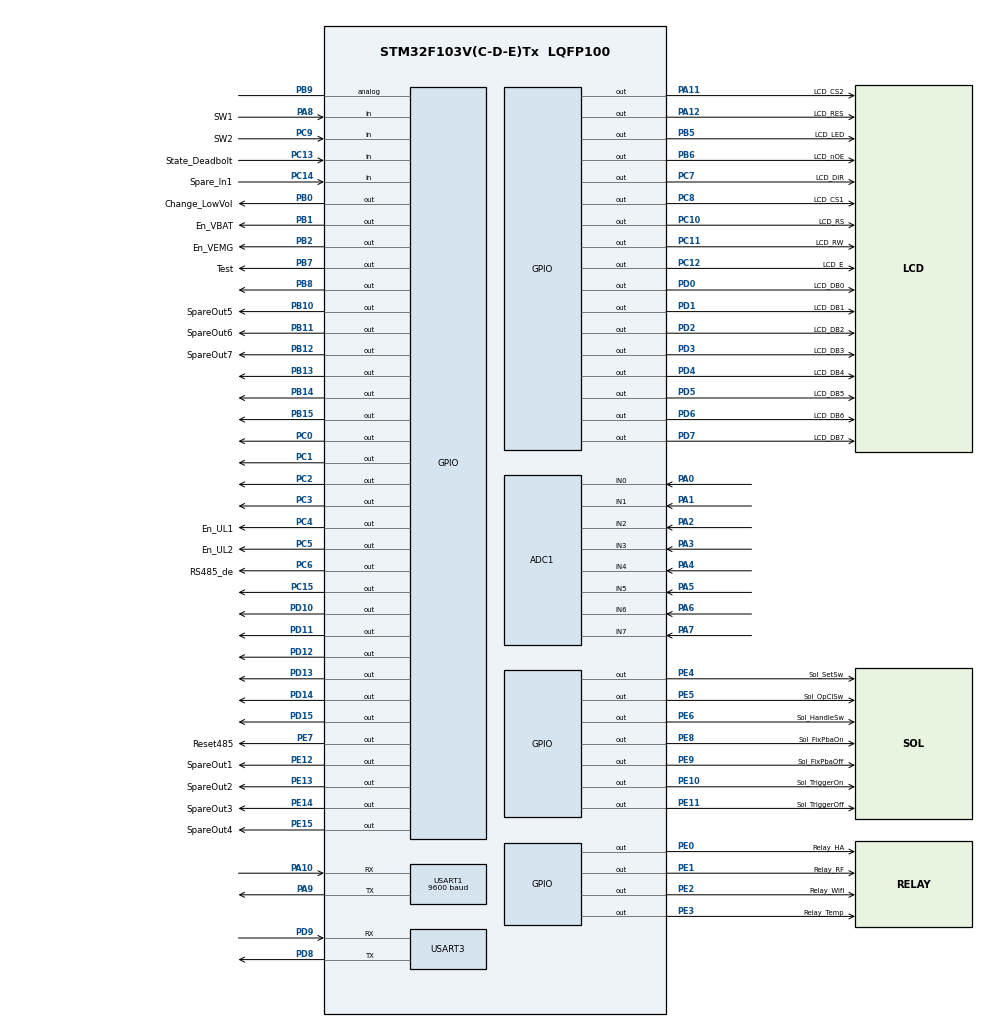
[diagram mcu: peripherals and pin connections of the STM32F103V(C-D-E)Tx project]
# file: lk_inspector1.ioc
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ADC1.Channel-0\#ChannelRegularConversion=ADC_CHANNEL_0
ADC1.NbrOfConversionFlag=1
ADC1.Rank-0\#ChannelRegularConversion=1
ADC1.SamplingTime-0\#ChannelRegularConversion=ADC_SAMPLETIME_1CYCLE_5
ADC1.master=1
FREERTOS.INCLUDE_pcTaskGetTaskName=1
FREERTOS.INCLUDE_xTaskGetCurrentTaskHandle=1
FREERTOS.INCLUDE_xTaskGetHandle=1
FREERTOS.Tasks01=defaultTask,24,128,StartDefaultTask,Default,NULL,Dynamic,NULL,NULL
FREERTOS.configUSE_IDLE_HOOK=1
FREERTOS.configUSE_NEWLIB_REENTRANT=0
Mcu.Family=STM32F1
Mcu.Name=STM32F103V(C-D-E)Tx
Mcu.Package=LQFP100
NVIC.PriorityGroup=NVIC_PRIORITYGROUP_4
NVIC.USART1_IRQn=true\:5\:0\:false\:false\:true\:true\:true\:true
OSC_IN.Mode=HSE-External-Oscillator
OSC_IN.Signal=RCC_OSC_IN
OSC_OUT.Mode=HSE-External-Oscillator
OSC_OUT.Signal=RCC_OSC_OUT
PA0-WKUP.Signal=ADCx_IN0
PA1.Signal=ADCx_IN1
PA10.Mode=Asynchronous
PA10.Signal=USART1_RX
PA11.GPIO_Label=LCD_CS2
PA11.Signal=GPIO_Output
PA12.GPIO_Label=LCD_RES
PA12.Signal=GPIO_Output
PA13.Mode=JTAG_5_pins
PA13.Signal=SYS_JTMS-SWDIO
PA14.Mode=JTAG_5_pins
PA14.Signal=SYS_JTCK-SWCLK
PA15.Mode=JTAG_5_pins
PA15.Signal=SYS_JTDI
PA2.Signal=ADCx_IN2
PA3.Signal=ADCx_IN3
PA4.Signal=ADCx_IN4
PA5.Signal=ADCx_IN5
PA6.Signal=ADCx_IN6
PA7.Signal=ADCx_IN7
PA8.GPIO_Label=SW1
PA8.Signal=GPIO_Input
PA9.Mode=Asynchronous
PA9.Signal=USART1_TX
PB0.GPIO_Label=Change_LowVol
PB0.Signal=GPIO_Output
PB1.GPIO_Label=En_VBAT
PB1.Signal=GPIO_Output
PB10.GPIO_Label=SpareOut5
PB10.Signal=GPIO_Output
PB11.GPIO_Label=SpareOut6
PB11.Signal=GPIO_Output
PB12.GPIO_Label=SpareOut7
PB12.Signal=GPIO_Output
PB13.Signal=GPIO_Output
PB14.Signal=GPIO_Output
PB15.Signal=GPIO_Output
PB2.GPIO_Label=En_VEMG
PB2.Signal=GPIO_Output
PB3.Mode=JTAG_5_pins
PB3.Signal=SYS_JTDO-TRACESWO
PB4.Mode=JTAG_5_pins
PB4.Signal=SYS_NJTRST
PB5.GPIO_Label=LCD_LED
PB5.Signal=GPIO_Output
PB6.GPIO_Label=LCD_nOE
PB6.Signal=GPIO_Output
PB7.GPIO_Label=Test
PB7.Signal=GPIO_Output
PB8.Signal=GPIO_Output
PB9.Signal=GPIO_Analog
PC0.Signal=GPIO_Output
PC1.Signal=GPIO_Output
PC10.GPIO_Label=LCD_RS
PC10.Signal=GPIO_Output
PC11.GPIO_Label=LCD_RW
PC11.Signal=GPIO_Output
PC12.GPIO_Label=LCD_E
PC12.Signal=GPIO_Output
PC13-TAMPER-RTC.GPIO_Label=State_Deadbolt
PC13-TAMPER-RTC.Signal=GPIO_Input
PC14-OSC32_IN.GPIO_Label=Spare_In1
PC14-OSC32_IN.Signal=GPIO_Input
PC15-OSC32_OUT.Signal=GPIO_Output
PC2.Signal=GPIO_Output
PC3.Signal=GPIO_Output
PC4.GPIO_Label=En_UL1
PC4.PinState=GPIO_PIN_SET
PC4.Signal=GPIO_Output
PC5.GPIO_Label=En_UL2
PC5.PinState=GPIO_PIN_SET
PC5.Signal=GPIO_Output
PC6.GPIO_Label=RS485_de
PC6.Signal=GPIO_Output
PC7.GPIO_Label=LCD_DIR
PC7.Signal=GPIO_Output
PC8.GPIO_Label=LCD_CS1
PC8.Signal=GPIO_Output
PC9.GPIO_Label=SW2
PC9.Signal=GPIO_Input
PD0.GPIO_Label=LCD_DB0
PD0.Signal=GPIO_Output
PD1.GPIO_Label=LCD_DB1
PD1.Signal=GPIO_Output
PD10.Signal=GPIO_Output
PD11.Signal=GPIO_Output
PD12.Signal=GPIO_Output
PD13.Signal=GPIO_Output
PD14.Signal=GPIO_Output
PD15.Signal=GPIO_Output
PD2.GPIO_Label=LCD_DB2
PD2.Signal=GPIO_Output
PD3.GPIO_Label=LCD_DB3
PD3.Signal=GPIO_Output
PD4.GPIO_Label=LCD_DB4
PD4.Signal=GPIO_Output
PD5.GPIO_Label=LCD_DB5
PD5.Signal=GPIO_Output
PD6.GPIO_Label=LCD_DB6
PD6.Signal=GPIO_Output
PD7.GPIO_Label=LCD_DB7
PD7.Signal=GPIO_Output
PD8.Mode=Asynchronous
PD8.Signal=USART3_TX
PD9.Mode=Asynchronous
PD9.Signal=USART3_RX
PE0.GPIO_Label=Relay_HA
PE0.Signal=GPIO_Output
PE1.GPIO_Label=Relay_RF
PE1.Signal=GPIO_Output
PE10.GPIO_Label=Sol_TriggerOn
PE10.Signal=GPIO_Output
PE11.GPIO_Label=Sol_TriggerOff
PE11.Signal=GPIO_Output
PE12.GPIO_Label=SpareOut1
PE12.Signal=GPIO_Output
PE13.GPIO_Label=SpareOut2
PE13.Signal=GPIO_Output
PE14.GPIO_Label=SpareOut3
PE14.Signal=GPIO_Output
PE15.GPIO_Label=SpareOut4
PE15.Signal=GPIO_Output
PE2.GPIO_Label=Relay_Wifi
PE2.Signal=GPIO_Output
PE3.GPIO_Label=Relay_Temp
PE3.Signal=GPIO_Output
PE4.GPIO_Label=Sol_SetSw
PE4.Signal=GPIO_Output
PE5.GPIO_Label=Sol_OpClSw
PE5.Signal=GPIO_Output
PE6.GPIO_Label=Sol_HandleSw
PE6.Signal=GPIO_Output
PE7.GPIO_Label=Reset485
PE7.Signal=GPIO_Output
PE8.GPIO_Label=Sol_FixPbaOn
PE8.Signal=GPIO_Output
PE9.GPIO_Label=Sol_FixPbaOff
PE9.Signal=GPIO_Output
ProjectManager.HeapSize=0x200
ProjectManager.StackSize=0x400
ProjectManager.TargetToolchain=STM32CubeIDE
RCC.APB1Freq_Value=8000000
RCC.APB2Freq_Value=8000000
SH.ADCx_IN0.0=ADC1_IN0,IN0
SH.ADCx_IN1.0=ADC1_IN1,IN1
SH.ADCx_IN2.0=ADC1_IN2,IN2
SH.ADCx_IN3.0=ADC1_IN3,IN3
SH.ADCx_IN4.0=ADC1_IN4,IN4
SH.ADCx_IN5.0=ADC1_IN5,IN5
SH.ADCx_IN6.0=ADC1_IN6,IN6
SH.ADCx_IN7.0=ADC1_IN7,IN7
TIM6.AutoReloadPreload=TIM_AUTORELOAD_PRELOAD_ENABLE
USART1.BaudRate=9600
USART1.VirtualMode=VM_ASYNC
USART3.VirtualMode=VM_ASYNC
VP_FREERTOS_VS_CMSIS_V2.Mode=CMSIS_V2
VP_TIM1_VS_ClockSourceINT.Mode=Internal
VP_TIM1_VS_ClockSourceITR.Mode=TriggerSource_ITR0
VP_TIM2_VS_ClockSourceINT.Mode=Internal
VP_TIM2_VS_ClockSourceITR.Mode=TriggerSource_ITR1
VP_TIM3_VS_ClockSourceINT.Mode=Internal
VP_TIM6_VS_ClockSourceINT.Mode=Enable_Timer
VP_TIM7_VS_ClockSourceINT.Mode=Enable_Timer
board=custom

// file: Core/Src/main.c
/* USER CODE BEGIN Header */
/**
  ******************************************************************************
  * @file           : main.c
  * @brief          : Main program body
  ******************************************************************************
  * @attention
  *
  * <h2><center>&copy; Copyright (c) 2020 STMicroelectronics.
  * All rights reserved.</center></h2>
  *
  * This software component is licensed by ST under BSD 3-Clause license,
  * the "License"; You may not use this file except in compliance with the
  * License. You may obtain a copy of the License at:
  *                        opensource.org/licenses/BSD-3-Clause
  *
  ******************************************************************************
  */
/* USER CODE END Header */
#include "main.h"
#include "cmsis_os.h"

/* USER CODE BEGIN Includes */
#include "my_generic.h"
#include "define_consts.h"
#include "taskDeviceh.h"
#include "functionh.h"
/* USER CODE END Includes */

/* USER CODE BEGIN PTD */
typedef StaticTask_t osStaticThreadDef_t;
// typedef StaticTimer_t osStaticTimerDef_t;
typedef StaticEventGroup_t osStaticEventGroupDef_t;

extern uint16_t gu16TimerInput[SW_vMAX];
extern uint16_t gu16TimerJob, gu16TimerLcd;
/* USER CODE END PTD */

/* USER CODE BEGIN PD */
ADC_HandleTypeDef hadc1;
// IWDG_HandleTypeDef hiwdg;

TIM_HandleTypeDef htim1;
TIM_HandleTypeDef htim2;
TIM_HandleTypeDef htim3;
TIM_HandleTypeDef htim6;
TIM_HandleTypeDef htim7;
UART_HandleTypeDef huart1;
UART_HandleTypeDef huart3;
// WWDG_HandleTypeDef hwwdg;

WORD_VAL gu16Flag1;
/* USER CODE END PD */

/* Definitions for defaultTask */
// osThreadId_t defaultTaskHandle;
// const osThreadAttr_t defaultTask_attributes = {
//   .name = "defaultTask",
//   .priority = (osPriority_t) osPriorityNormal,
//   .stack_size = 128 * 4
// };
/* Definitions for PortTimer */
osTimerId_t PortTimerHandle;
const osTimerAttr_t PortTimer_attributes = {
  .name = "PortTimer"
};
/* USER CODE BEGIN PV */
/* Definitions for defaultTask */
osThreadId_t FunctionJobHandle;
const osThreadAttr_t FunctionJob_attributes = {
  .name = "FunctionJob",
  .priority = (osPriority_t) osPriorityNormal,
  .stack_size = 128 * 4
};
/* Definitions for LcdTask */
osThreadId_t LcdTaskHandle;
// uint32_t gu32LcdTaskBuffer[ 128 ];
// osStaticThreadDef_t myTask02ControlBlock;
const osThreadAttr_t myTask02_attributes = {
  .name = "LcdTask",
  // .stack_mem = &gu32LcdTaskBuffer[0],
  // .stack_size = sizeof(gu32LcdTaskBuffer),
  // .cb_mem = &myTask02ControlBlock,
  // .cb_size = sizeof(myTask02ControlBlock),
  .priority = (osPriority_t) osPriorityNormal,//osPriorityLow,
  .stack_size = 128 * 4
};
osThreadId_t DeviceTaskHandle;
const osThreadAttr_t DeviceTask_attributes = {
  .name = "TaskForDevice",
  .priority = (osPriority_t) osPriorityNormal,
  .stack_size = 128 * 4
};

/* Definitions for myTimer01 */
// osTimerId_t InputTimerHandle;//myTimer01Handle;
// osStaticTimerDef_t myTimer01ControlBlock;
// const osTimerAttr_t myTimer01_attributes = {
//   .name = "myTimer01",
//   .cb_mem = &myTimer01ControlBlock,
//   .cb_size = sizeof(myTimer01ControlBlock),
// };

/* Definitions for FlagEvent01 */
osEventFlagsId_t FlagEvent01Handle;
osStaticEventGroupDef_t myEvent01ControlBlock;
const osEventFlagsAttr_t FlagEvent01_attributes = {
  .name = "FlagEvent01",
  .cb_mem = &myEvent01ControlBlock,
  .cb_size = sizeof(myEvent01ControlBlock),
};
/* Definitions for myEvent02 */
osEventFlagsId_t myEvent02Handle;
osStaticEventGroupDef_t myEvent02ControlBlock;
const osEventFlagsAttr_t myEvent02_attributes = {
  .name = "myEvent02",
  .cb_mem = &myEvent02ControlBlock,
  .cb_size = sizeof(myEvent02ControlBlock),
};
/* USER CODE END PV */

void SystemClock_Config(void);
// void StartDefaultTask(void *argument);
void CheckPortTimer(void *argument);

/* USER CODE BEGIN PFP */

// static void MX_GPIO_Init(void);
void MX_GPIO_Init(void);
void MX_ADC1_Init(void);
// static void MX_IWDG_Init(void);
static void MX_TIM1_Init(void);
static void MX_TIM2_Init(void);
static void MX_TIM3_Init(void);
// static void MX_WWDG_Init(void);
static void MX_TIM6_Init(void);
static void MX_TIM7_Init(void);
static void MX_USART1_UART_Init(void);
static void MX_USART3_UART_Init(void);

/* USER CODE END PFP */

int main(void)
{

  /* MCU Configuration--------------------------------------------------------*/

  /* Reset of all peripherals, Initializes the Flash interface and the Systick. */

	 HAL_Init();

  /* Configure the system clock */
  SystemClock_Config();

  /* Initialize all configured peripherals */
  /* USER CODE BEGIN 2 */
  MX_GPIO_Init();
  MX_ADC1_Init();
  // MX_IWDG_Init(); //HAL_IWDG_Refresh(&hiwdg);
  MX_TIM1_Init();
  MX_TIM2_Init();
  MX_TIM3_Init();
  // MX_WWDG_Init(); //HAL_WWDG_Refresh(hwwdg);
  MX_TIM6_Init();
  MX_TIM7_Init();
  MX_USART1_UART_Init();
  MX_USART3_UART_Init();
  ResetADCData();
  /* USER CODE END 2 */

  /* Init scheduler */
  osKernelInitialize();

  /* USER CODE BEGIN RTOS_TIMERS */
  /* start timers, add new ones, ... */
  /* Create the timer(s) */
  /* creation of PortTimer */
  PortTimerHandle = osTimerNew(CheckPortTimer, osTimerPeriodic, NULL, &PortTimer_attributes);
  osTimerStart(PortTimerHandle,10);
  /* USER CODE END RTOS_TIMERS */

  /* Create the thread(s) */
  /* creation of defaultTask */
  // defaultTaskHandle = osThreadNew(StartDefaultTask, NULL, &defaultTask_attributes);

  FunctionJobHandle = osThreadNew(defaultJob, NULL, &FunctionJob_attributes);// FunctionJob
  LcdTaskHandle = osThreadNew(DisplayTask, NULL, &myTask02_attributes);
  DeviceTaskHandle = osThreadNew(DeviceTask, NULL, &DeviceTask_attributes);

  /* USER CODE BEGIN RTOS_EVENTS */
  /* add events, ... */
  myEvent02Handle = osEventFlagsNew(&myEvent02_attributes);
  FlagEvent01Handle = osEventFlagsNew(&FlagEvent01_attributes);
  /* USER CODE END RTOS_EVENTS */

  /* Start scheduler */
  osKernelStart();

  /* We should never get here as control is now taken by the scheduler */
  /* Infinite loop */
  while (1)
  {

  }
}

void SystemClock_Config(void)
{
  RCC_OscInitTypeDef RCC_OscInitStruct = {0};
  RCC_ClkInitTypeDef RCC_ClkInitStruct = {0};
  RCC_PeriphCLKInitTypeDef PeriphClkInit = {0};

  /** Initializes the RCC Oscillators according to the specified parameters
  * in the RCC_OscInitTypeDef structure.
  */
  RCC_OscInitStruct.OscillatorType = RCC_OSCILLATORTYPE_HSI;
  RCC_OscInitStruct.HSIState = RCC_HSI_ON;
  RCC_OscInitStruct.HSICalibrationValue = RCC_HSICALIBRATION_DEFAULT;
  RCC_OscInitStruct.PLL.PLLState = RCC_PLL_NONE;
  if (HAL_RCC_OscConfig(&RCC_OscInitStruct) != HAL_OK)
  {
    Error_Handler();
  }
  /** Initializes the CPU, AHB and APB buses clocks
  */
  RCC_ClkInitStruct.ClockType = RCC_CLOCKTYPE_HCLK|RCC_CLOCKTYPE_SYSCLK
                               |RCC_CLOCKTYPE_PCLK1|RCC_CLOCKTYPE_PCLK2;
  RCC_ClkInitStruct.SYSCLKSource = RCC_SYSCLKSOURCE_HSI;
  RCC_ClkInitStruct.AHBCLKDivider = RCC_SYSCLK_DIV1;
  RCC_ClkInitStruct.APB1CLKDivider = RCC_HCLK_DIV1;
  RCC_ClkInitStruct.APB2CLKDivider = RCC_HCLK_DIV1;

  if (HAL_RCC_ClockConfig(&RCC_ClkInitStruct, FLASH_LATENCY_0) != HAL_OK)
  {
    Error_Handler();
  }
  PeriphClkInit.PeriphClockSelection = RCC_PERIPHCLK_ADC;
  PeriphClkInit.AdcClockSelection = RCC_ADCPCLK2_DIV2;
  if (HAL_RCCEx_PeriphCLKConfig(&PeriphClkInit) != HAL_OK)
  {
    Error_Handler();
  }
}

/* USER CODE BEGIN 4 */

void MX_ADC1_Init(void)
{

  ADC_ChannelConfTypeDef sConfig = {0};

  /** Common config
  */
  hadc1.Instance = ADC1;
  hadc1.Init.ScanConvMode = ADC_SCAN_DISABLE;
  hadc1.Init.ContinuousConvMode = DISABLE;
  hadc1.Init.DiscontinuousConvMode = DISABLE;//ENABLE;//DISABLE;
  hadc1.Init.ExternalTrigConv = ADC_SOFTWARE_START;
  hadc1.Init.DataAlign = ADC_DATAALIGN_RIGHT;
  hadc1.Init.NbrOfConversion = 1;
  if (HAL_ADC_Init(&hadc1) != HAL_OK)
  {
    Error_Handler();
  }
  /** Configure Regular Channel **/
  sConfig.Channel = ADC_CHANNEL_0;
  sConfig.Rank = ADC_REGULAR_RANK_1;
  sConfig.SamplingTime = ADC_SAMPLETIME_1CYCLE_5;
  if (HAL_ADC_ConfigChannel(&hadc1, &sConfig) != HAL_OK)
  {
    Error_Handler();
  }

}
static void MX_TIM1_Init(void)
{

  TIM_ClockConfigTypeDef sClockSourceConfig = {0};
  TIM_SlaveConfigTypeDef sSlaveConfig = {0};
  TIM_MasterConfigTypeDef sMasterConfig = {0};

  htim1.Instance = TIM1;
  htim1.Init.Prescaler = 0;
  htim1.Init.CounterMode = TIM_COUNTERMODE_UP;
  htim1.Init.Period = 65535;
  htim1.Init.ClockDivision = TIM_CLOCKDIVISION_DIV1;
  htim1.Init.RepetitionCounter = 0;
  htim1.Init.AutoReloadPreload = TIM_AUTORELOAD_PRELOAD_DISABLE;
  if (HAL_TIM_Base_Init(&htim1) != HAL_OK)
  {
    Error_Handler();
  }
  sClockSourceConfig.ClockSource = TIM_CLOCKSOURCE_INTERNAL;
  if (HAL_TIM_ConfigClockSource(&htim1, &sClockSourceConfig) != HAL_OK)
  {
    Error_Handler();
  }
  sSlaveConfig.SlaveMode = TIM_SLAVEMODE_DISABLE;
  sSlaveConfig.InputTrigger = TIM_TS_ITR0;
  if (HAL_TIM_SlaveConfigSynchro(&htim1, &sSlaveConfig) != HAL_OK)
  {
    Error_Handler();
  }
  sMasterConfig.MasterOutputTrigger = TIM_TRGO_RESET;
  sMasterConfig.MasterSlaveMode = TIM_MASTERSLAVEMODE_DISABLE;
  if (HAL_TIMEx_MasterConfigSynchronization(&htim1, &sMasterConfig) != HAL_OK)
  {
    Error_Handler();
  }

}

static void MX_TIM2_Init(void)
{

  TIM_ClockConfigTypeDef sClockSourceConfig = {0};
  TIM_SlaveConfigTypeDef sSlaveConfig = {0};
  TIM_MasterConfigTypeDef sMasterConfig = {0};

  htim2.Instance = TIM2;
  htim2.Init.Prescaler = 0;
  htim2.Init.CounterMode = TIM_COUNTERMODE_UP;
  htim2.Init.Period = 65535;
  htim2.Init.ClockDivision = TIM_CLOCKDIVISION_DIV1;
  htim2.Init.AutoReloadPreload = TIM_AUTORELOAD_PRELOAD_DISABLE;
  if (HAL_TIM_Base_Init(&htim2) != HAL_OK)
  {
    Error_Handler();
  }
  sClockSourceConfig.ClockSource = TIM_CLOCKSOURCE_INTERNAL;
  if (HAL_TIM_ConfigClockSource(&htim2, &sClockSourceConfig) != HAL_OK)
  {
    Error_Handler();
  }
  sSlaveConfig.SlaveMode = TIM_SLAVEMODE_DISABLE;
  sSlaveConfig.InputTrigger = TIM_TS_ITR1;
  if (HAL_TIM_SlaveConfigSynchro(&htim2, &sSlaveConfig) != HAL_OK)
  {
    Error_Handler();
  }
  sMasterConfig.MasterOutputTrigger = TIM_TRGO_RESET;
  sMasterConfig.MasterSlaveMode = TIM_MASTERSLAVEMODE_DISABLE;
  if (HAL_TIMEx_MasterConfigSynchronization(&htim2, &sMasterConfig) != HAL_OK)
  {
    Error_Handler();
  }

}

static void MX_TIM3_Init(void)
{

  TIM_ClockConfigTypeDef sClockSourceConfig = {0};
  TIM_MasterConfigTypeDef sMasterConfig = {0};

  htim3.Instance = TIM3;
  htim3.Init.Prescaler = 0;
  htim3.Init.CounterMode = TIM_COUNTERMODE_UP;
  htim3.Init.Period = 65535;
  htim3.Init.ClockDivision = TIM_CLOCKDIVISION_DIV1;
  htim3.Init.AutoReloadPreload = TIM_AUTORELOAD_PRELOAD_DISABLE;
  if (HAL_TIM_Base_Init(&htim3) != HAL_OK)
  {
    Error_Handler();
  }
  sClockSourceConfig.ClockSource = TIM_CLOCKSOURCE_INTERNAL;
  if (HAL_TIM_ConfigClockSource(&htim3, &sClockSourceConfig) != HAL_OK)
  {
    Error_Handler();
  }
  sMasterConfig.MasterOutputTrigger = TIM_TRGO_RESET;
  sMasterConfig.MasterSlaveMode = TIM_MASTERSLAVEMODE_DISABLE;
  if (HAL_TIMEx_MasterConfigSynchronization(&htim3, &sMasterConfig) != HAL_OK)
  {
    Error_Handler();
  }

}

static void MX_TIM6_Init(void)
{

  TIM_MasterConfigTypeDef sMasterConfig = {0};

  htim6.Instance = TIM6;
  htim6.Init.Prescaler = 0;
  htim6.Init.CounterMode = TIM_COUNTERMODE_UP;
  htim6.Init.Period = 65535;
  htim6.Init.AutoReloadPreload = TIM_AUTORELOAD_PRELOAD_ENABLE;
  if (HAL_TIM_Base_Init(&htim6) != HAL_OK)
  {
    Error_Handler();
  }
  sMasterConfig.MasterOutputTrigger = TIM_TRGO_RESET;
  sMasterConfig.MasterSlaveMode = TIM_MASTERSLAVEMODE_DISABLE;
  if (HAL_TIMEx_MasterConfigSynchronization(&htim6, &sMasterConfig) != HAL_OK)
  {
    Error_Handler();
  }

}

static void MX_TIM7_Init(void)
{

  TIM_MasterConfigTypeDef sMasterConfig = {0};

  htim7.Instance = TIM7;
  htim7.Init.Prescaler = 0;
  htim7.Init.CounterMode = TIM_COUNTERMODE_UP;
  htim7.Init.Period = 65535;
  htim7.Init.AutoReloadPreload = TIM_AUTORELOAD_PRELOAD_DISABLE;
  if (HAL_TIM_Base_Init(&htim7) != HAL_OK)
  {
    Error_Handler();
  }
  sMasterConfig.MasterOutputTrigger = TIM_TRGO_RESET;
  sMasterConfig.MasterSlaveMode = TIM_MASTERSLAVEMODE_DISABLE;
  if (HAL_TIMEx_MasterConfigSynchronization(&htim7, &sMasterConfig) != HAL_OK)
  {
    Error_Handler();
  }

}

static void MX_USART1_UART_Init(void)
{

  huart1.Instance = USART1;
  huart1.Init.BaudRate = 9600;
  huart1.Init.WordLength = UART_WORDLENGTH_8B;
  huart1.Init.StopBits = UART_STOPBITS_1;
  huart1.Init.Parity = UART_PARITY_NONE;
  huart1.Init.Mode = UART_MODE_TX_RX;
  huart1.Init.HwFlowCtl = UART_HWCONTROL_NONE;
  huart1.Init.OverSampling = UART_OVERSAMPLING_16;
  if (HAL_UART_Init(&huart1) != HAL_OK)
  {
    Error_Handler();
  }
  /* USER CODE BEGIN USART1_Init 2 */
  __HAL_UART_ENABLE_IT(&huart1, UART_IT_RXNE);
  /* USER CODE END USART1_Init 2 */

}

static void MX_USART3_UART_Init(void)
{

  huart3.Instance = USART3;
  huart3.Init.BaudRate = 115200;
  huart3.Init.WordLength = UART_WORDLENGTH_8B;
  huart3.Init.StopBits = UART_STOPBITS_1;
  huart3.Init.Parity = UART_PARITY_NONE;
  huart3.Init.Mode = UART_MODE_TX_RX;
  huart3.Init.HwFlowCtl = UART_HWCONTROL_NONE;
  huart3.Init.OverSampling = UART_OVERSAMPLING_16;
  if (HAL_UART_Init(&huart3) != HAL_OK)
  {
    Error_Handler();
  }

}

// static void MX_WWDG_Init(void)
// {

//   /* USER CODE BEGIN WWDG_Init 0 */
//   __HAL_DBGMCU_FREEZE_WWDG();
//   /* USER CODE END WWDG_Init 0 */

//   /* USER CODE BEGIN WWDG_Init 1 */

//   /* USER CODE END WWDG_Init 1 */
//   hwwdg.Instance = WWDG;
//   hwwdg.Init.Prescaler = WWDG_PRESCALER_8;
//   hwwdg.Init.Window = 64;
//   hwwdg.Init.Counter = 64;
//   hwwdg.Init.EWIMode = WWDG_EWI_DISABLE;
//   if (HAL_WWDG_Init(&hwwdg) != HAL_OK)
//   {
//     Error_Handler();
//   }
//   /* USER CODE BEGIN WWDG_Init 2 */
//   if(__HAL_RCC_GET_FLAG(RCC_FLAG_WWDGRST) == SET)
//   {
// 	  __HAL_RCC_CLEAR_RESET_FLAGS();
//   }
//   /* USER CODE END WWDG_Init 2 */

// }

// static void MX_GPIO_Init(void)
void MX_GPIO_Init(void)
{
  GPIO_InitTypeDef GPIO_InitStruct = {0};

  /* GPIO Ports Clock Enable */
  __HAL_RCC_GPIOE_CLK_ENABLE();
  __HAL_RCC_GPIOC_CLK_ENABLE();
  __HAL_RCC_GPIOA_CLK_ENABLE();
  __HAL_RCC_GPIOB_CLK_ENABLE();
  __HAL_RCC_GPIOD_CLK_ENABLE();

  /*Configure GPIO pin Output Level */
  HAL_GPIO_WritePin(GPIOE, Relay_Wifi_Pin|Relay_Temp_Pin|Sol_SetSw_Pin|Sol_OpClSw_Pin
                          |Sol_HandleSw_Pin|Reset485_Pin|Sol_FixPbaOn_Pin|Sol_OpClSw_Pin2
                          |Sol_TriggerOn_Pin|Sol_TriggerOff_Pin|SpareOut1_Pin|SpareOut2_Pin
                          |SpareOut3_Pin|SpareOut4_Pin|Relay_HA_Pin|Relay_RF_Pin, GPIO_PIN_RESET);

  /*Configure GPIO pin Output Level */
  HAL_GPIO_WritePin(GPIOC, GPIO_PIN_15|GPIO_PIN_0|GPIO_PIN_1|GPIO_PIN_2
                          |GPIO_PIN_3|RS485_de_Pin|LCD_CS1_Pin
                          |LCD_E_Pin, GPIO_PIN_RESET);

  /*Configure GPIO pin Output Level */
  HAL_GPIO_WritePin(GPIOC, En_UL1_Pin|En_UL2_Pin|LCD_RS_Pin|LCD_DIR_Pin|LCD_RW_Pin, GPIO_PIN_SET);

  /*Configure GPIO pin Output Level */
  HAL_GPIO_WritePin(GPIOB, Change_LowVol_Pin|En_VBAT_Pin|En_VEMG_Pin|SpareOut5_Pin
                          |SpareOut6_Pin|SpareOut7_Pin|GPIO_PIN_13|GPIO_PIN_14
                          |GPIO_PIN_15|LCD_LED_Pin|Test_Pin
                          |GPIO_PIN_8, GPIO_PIN_RESET);
  HAL_GPIO_WritePin(GPIOB, LCD_nOE_Pin, GPIO_PIN_SET);

  /*Configure GPIO pin Output Level */
  HAL_GPIO_WritePin(GPIOD, GPIO_PIN_10|GPIO_PIN_11|GPIO_PIN_12|GPIO_PIN_13
                          |GPIO_PIN_14|GPIO_PIN_15|LCD_DB0_Pin|LCD_DB1_Pin
                          |LCD_DB2_Pin|LCD_DB3_Pin|LCD_DB4_Pin|LCD_DB5_Pin
                          |LCD_DB6_Pin|LCD_DB7_Pin, GPIO_PIN_RESET);

  /*Configure GPIO pin Output Level */
  HAL_GPIO_WritePin(GPIOA, LCD_CS2_Pin, GPIO_PIN_RESET);
  HAL_GPIO_WritePin(GPIOA, (LCD_RES_Pin | Uart1Tx_Pin |Uart1Rx_Pin), GPIO_PIN_SET);

  /*Configure GPIO pins : Relay_Wifi_Pin Relay_Temp_Pin Sol_SetSw_Pin Sol_OpClSw_Pin
                           Sol_HandleSw_Pin Reset485_Pin Sol_FixPbaOn_Pin Sol_FixPbaOff_Pin
                           Sol_TriggerOn_Pin Sol_TriggerOff_Pin SpareOut1_Pin SpareOut2_Pin
                           SpareOut3_Pin SpareOut4_Pin Relay_HA_Pin Relay_RF_Pin */
  GPIO_InitStruct.Pin = Relay_Wifi_Pin|Relay_Temp_Pin|Sol_SetSw_Pin|Sol_OpClSw_Pin
                          |Sol_HandleSw_Pin|Reset485_Pin|Sol_FixPbaOn_Pin|Sol_OpClSw_Pin2
                          |Sol_TriggerOn_Pin|Sol_TriggerOff_Pin|SpareOut1_Pin|SpareOut2_Pin
                          |SpareOut3_Pin|SpareOut4_Pin|Relay_HA_Pin|Relay_RF_Pin;
  GPIO_InitStruct.Mode = GPIO_MODE_OUTPUT_PP;
  GPIO_InitStruct.Pull = GPIO_NOPULL;
  GPIO_InitStruct.Speed = GPIO_SPEED_FREQ_LOW;
  HAL_GPIO_Init(GPIOE, &GPIO_InitStruct);

  /*Configure GPIO pins : State_Deadbolt_Pin Spare_In1_Pin SW2_Pin */
  GPIO_InitStruct.Pin = State_Deadbolt_Pin|Spare_In1_Pin|SW2_Pin;
  GPIO_InitStruct.Mode = GPIO_MODE_INPUT;
  GPIO_InitStruct.Pull = GPIO_NOPULL;
  HAL_GPIO_Init(GPIOC, &GPIO_InitStruct);

  /*Configure GPIO pins : PC15 PC0 PC1 PC2
                           PC3 En_UL1_Pin En_UL2_Pin RS485_de_Pin
                           LCD_DIR_Pin LCD_CS1_Pin LCD_RS_Pin LCD_RW_Pin
                           LCD_E_Pin */
  GPIO_InitStruct.Pin = GPIO_PIN_15|GPIO_PIN_0|GPIO_PIN_1|GPIO_PIN_2
                          |GPIO_PIN_3|En_UL1_Pin|En_UL2_Pin|RS485_de_Pin
                          |LCD_DIR_Pin|LCD_CS1_Pin|LCD_RS_Pin|LCD_RW_Pin
                          |LCD_E_Pin;
  GPIO_InitStruct.Mode = GPIO_MODE_OUTPUT_PP;
  GPIO_InitStruct.Pull = GPIO_NOPULL;
  GPIO_InitStruct.Speed = GPIO_SPEED_FREQ_LOW;
  HAL_GPIO_Init(GPIOC, &GPIO_InitStruct);

  /*Configure GPIO pins : Change_LowVol_Pin En_VBAT_Pin En_VEMG_Pin SpareOut5_Pin
                           SpareOut6_Pin SpareOut7_Pin PB13 PB14
                           PB15 LCD_LED_Pin LCD_nOE_Pin Test_Pin
                           PB8 */
  GPIO_InitStruct.Pin = Change_LowVol_Pin|En_VBAT_Pin|En_VEMG_Pin|SpareOut5_Pin
                          |SpareOut6_Pin|SpareOut7_Pin|GPIO_PIN_13|GPIO_PIN_14
                          |GPIO_PIN_15|LCD_LED_Pin|LCD_nOE_Pin|Test_Pin
                          |GPIO_PIN_8;
  GPIO_InitStruct.Mode = GPIO_MODE_OUTPUT_PP;
  GPIO_InitStruct.Pull = GPIO_NOPULL;
  GPIO_InitStruct.Speed = GPIO_SPEED_FREQ_LOW;
  HAL_GPIO_Init(GPIOB, &GPIO_InitStruct);

  /*Configure GPIO pins : PD10 PD11 PD12 PD13
                           PD14 PD15 LCD_DB0_Pin LCD_DB1_Pin
                           LCD_DB2_Pin LCD_DB3_Pin LCD_DB4_Pin LCD_DB5_Pin
                           LCD_DB6_Pin LCD_DB7_Pin */
  GPIO_InitStruct.Pin = GPIO_PIN_10|GPIO_PIN_11|GPIO_PIN_12|GPIO_PIN_13
                          |GPIO_PIN_14|GPIO_PIN_15|LCD_DB0_Pin|LCD_DB1_Pin
                          |LCD_DB2_Pin|LCD_DB3_Pin|LCD_DB4_Pin|LCD_DB5_Pin
                          |LCD_DB6_Pin|LCD_DB7_Pin;
  GPIO_InitStruct.Mode = GPIO_MODE_OUTPUT_PP;
  GPIO_InitStruct.Pull = GPIO_NOPULL;
  GPIO_InitStruct.Speed = GPIO_SPEED_FREQ_LOW;
  HAL_GPIO_Init(GPIOD, &GPIO_InitStruct);

  /*Configure GPIO pin : SW1_Pin */
  GPIO_InitStruct.Pin = SW1_Pin;
  GPIO_InitStruct.Mode = GPIO_MODE_INPUT;
  GPIO_InitStruct.Pull = GPIO_NOPULL;
  HAL_GPIO_Init(SW1_GPIO_Port, &GPIO_InitStruct);

  /*Configure GPIO pins : LCD_CS2_Pin LCD_RES_Pin */
  GPIO_InitStruct.Pin = LCD_CS2_Pin|LCD_RES_Pin | Uart1Tx_Pin;
  GPIO_InitStruct.Mode = GPIO_MODE_OUTPUT_PP;
  GPIO_InitStruct.Pull = GPIO_NOPULL;
  GPIO_InitStruct.Speed = GPIO_SPEED_FREQ_LOW;
  HAL_GPIO_Init(GPIOA, &GPIO_InitStruct);

  GPIO_InitStruct.Pin = Uart1Rx_Pin;
  GPIO_InitStruct.Mode = GPIO_MODE_INPUT;
  GPIO_InitStruct.Pull = GPIO_PULLUP;
  HAL_GPIO_Init(Uart1_Port, &GPIO_InitStruct);

  /*Configure GPIO pin : PB9 */
  GPIO_InitStruct.Pin = GPIO_PIN_9;
  GPIO_InitStruct.Mode = GPIO_MODE_ANALOG;
  HAL_GPIO_Init(GPIOB, &GPIO_InitStruct);

}
/* USER CODE BEGIN */
/* CheckPortTimer function */
// 10mmS Timer
void CheckPortTimer(void *argument)
{
  /* USER CODE BEGIN CheckPortTimer */
  uint16_t u16TmpCnt;
  for(u16TmpCnt = 0; u16TmpCnt < SW_vMAX; u16TmpCnt++){
    ++gu16TimerInput[u16TmpCnt];
  }
  ++gu16TimerJob;
  ++gu16TimerLcd;
  /* USER CODE END CheckPortTimer */
}
/* USER CODE END */
void Error_Handler(void)
{
}

/************************ (C) COPYRIGHT STMicroelectronics *****END OF FILE****/

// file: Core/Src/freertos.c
/* USER CODE BEGIN Header */
/**
  ******************************************************************************
  * File Name          : freertos.c
  * Description        : Code for freertos applications
  ******************************************************************************
  * @attention
  *
  * <h2><center>&copy; Copyright (c) 2020 STMicroelectronics.
  * All rights reserved.</center></h2>
  *
  * This software component is licensed by ST under Ultimate Liberty license
  * SLA0044, the "License"; You may not use this file except in compliance with
  * the License. You may obtain a copy of the License at:
  *                             www.st.com/SLA0044
  *
  ******************************************************************************
  */
/* USER CODE END Header */

#include "FreeRTOS.h"
#include "task.h"
#include "main.h"

/* Hook prototypes */
void vApplicationIdleHook(void);

/* USER CODE BEGIN 2 */
__weak void vApplicationIdleHook( void )
{
   /* vApplicationIdleHook() will only be called if configUSE_IDLE_HOOK is set
   to 1 in FreeRTOSConfig.h. It will be called on each iteration of the idle
   task. It is essential that code added to this hook function never attempts
   to block in any way (for example, call xQueueReceive() with a block time
   specified, or call vTaskDelay()). If the application makes use of the
   vTaskDelete() API function (as this demo application does) then it is also
   important that vApplicationIdleHook() is permitted to return to its calling
   function, because it is the responsibility of the idle task to clean up
   memory allocated by the kernel to any task that has since been deleted. */
}
/* USER CODE END 2 */

/************************ (C) COPYRIGHT STMicroelectronics *****END OF FILE****/
